########################################################################
# Hand-written cell LEF for FRIDA analog primitive cells
#
# These are simplified physical abstracts for the sg13_lv_nmos and
# sg13_lv_pmos devices as generated by flow/mosfet/primitive.py with
# default MosfetParams (nf=4, w=1, l=1, vth=LOW, source_tie=OFF, pr=2).
#
# Cell size: 3.020 x 3.060 um (from KLayout bbox in dbu with dbu=0.001)
# Row height: 3.060 um (= SITE height, cells tile into standard rows)
#
# Pin positions (track-aligned, 0.420 x 0.420 um to span Metal1 pitch):
#   s:    (0.000, 0.000) -> (0.420, 0.420)   bottom-left (source/vss)
#   d:    (2.600, 0.630) -> (3.020, 1.050)   right-side  (drain)
#   g:    (0.000, 1.320) -> (0.420, 1.740)   left-side   (gate)
#   b:    (0.000, 2.640) -> (0.420, 3.060)   top-left    (bulk/vdd)
#
# NOTE: This is a temporary hand-written file for verifying that
# OpenROAD can read our design. The real flow will generate this
# from vlsir.raw via Layout21's LefExporter.
########################################################################

VERSION 5.7 ;
BUSBITCHARS "[]" ;
DIVIDERCHAR "/" ;

SITE unit
  SYMMETRY Y ;
  CLASS CORE ;
  SIZE 0.005 BY 3.060 ;
END unit

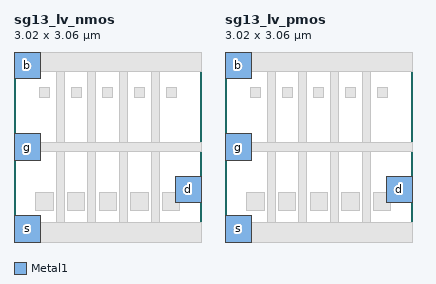
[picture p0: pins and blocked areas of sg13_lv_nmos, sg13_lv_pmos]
MACRO sg13_lv_nmos
  CLASS CORE ;
  ORIGIN 0 0 ;
  FOREIGN sg13_lv_nmos 0 0 ;
  SYMMETRY X Y ;
  SITE unit ;
  SIZE 3.020 BY 3.060 ;

  PIN d
    DIRECTION INOUT ;
    USE SIGNAL ;
    PORT
      LAYER Metal1 ;
        RECT 2.600 0.630 3.020 1.050 ;
    END
  END d

  PIN g
    DIRECTION INPUT ;
    USE SIGNAL ;
    PORT
      LAYER Metal1 ;
        RECT 0.000 1.320 0.420 1.740 ;
    END
  END g

  PIN s
    DIRECTION INOUT ;
    USE SIGNAL ;
    PORT
      LAYER Metal1 ;
        RECT 0.000 0.000 0.420 0.420 ;
    END
  END s

  PIN b
    DIRECTION INOUT ;
    USE SIGNAL ;
    PORT
      LAYER Metal1 ;
        RECT 0.000 2.640 0.420 3.060 ;
    END
  END b

  OBS
    LAYER GatPoly ;
      RECT 0.680 0.320 0.810 2.740 ;
      RECT 1.190 0.320 1.320 2.740 ;
      RECT 1.700 0.320 1.830 2.740 ;
      RECT 2.210 0.320 2.340 2.740 ;
    LAYER Cont ;
      RECT 0.410 0.570 0.570 0.730 ;
      RECT 0.410 2.330 0.570 2.490 ;
      RECT 0.920 0.570 1.080 0.730 ;
      RECT 0.920 2.330 1.080 2.490 ;
      RECT 1.430 0.570 1.590 0.730 ;
      RECT 1.430 2.330 1.590 2.490 ;
      RECT 1.940 0.570 2.100 0.730 ;
      RECT 1.940 2.330 2.100 2.490 ;
      RECT 2.450 0.570 2.610 0.730 ;
      RECT 2.450 2.330 2.610 2.490 ;
    LAYER Metal1 ;
      RECT 0.000 0.000 3.020 0.320 ;
      RECT 0.000 1.450 3.020 1.610 ;
      RECT 0.000 2.740 3.020 3.060 ;
      RECT 0.350 0.510 0.630 0.790 ;
      RECT 0.860 0.510 1.140 0.790 ;
      RECT 1.370 0.510 1.650 0.790 ;
      RECT 1.880 0.510 2.160 0.790 ;
      RECT 2.390 0.510 2.670 0.790 ;
  END

END sg13_lv_nmos

MACRO sg13_lv_pmos
  CLASS CORE ;
  ORIGIN 0 0 ;
  FOREIGN sg13_lv_pmos 0 0 ;
  SYMMETRY X Y ;
  SITE unit ;
  SIZE 3.020 BY 3.060 ;

  PIN d
    DIRECTION INOUT ;
    USE SIGNAL ;
    PORT
      LAYER Metal1 ;
        RECT 2.600 0.630 3.020 1.050 ;
    END
  END d

  PIN g
    DIRECTION INPUT ;
    USE SIGNAL ;
    PORT
      LAYER Metal1 ;
        RECT 0.000 1.320 0.420 1.740 ;
    END
  END g

  PIN s
    DIRECTION INOUT ;
    USE SIGNAL ;
    PORT
      LAYER Metal1 ;
        RECT 0.000 0.000 0.420 0.420 ;
    END
  END s

  PIN b
    DIRECTION INOUT ;
    USE SIGNAL ;
    PORT
      LAYER Metal1 ;
        RECT 0.000 2.640 0.420 3.060 ;
    END
  END b

  OBS
    LAYER GatPoly ;
      RECT 0.680 0.320 0.810 2.740 ;
      RECT 1.190 0.320 1.320 2.740 ;
      RECT 1.700 0.320 1.830 2.740 ;
      RECT 2.210 0.320 2.340 2.740 ;
    LAYER Cont ;
      RECT 0.410 0.570 0.570 0.730 ;
      RECT 0.410 2.330 0.570 2.490 ;
      RECT 0.920 0.570 1.080 0.730 ;
      RECT 0.920 2.330 1.080 2.490 ;
      RECT 1.430 0.570 1.590 0.730 ;
      RECT 1.430 2.330 1.590 2.490 ;
      RECT 1.940 0.570 2.100 0.730 ;
      RECT 1.940 2.330 2.100 2.490 ;
      RECT 2.450 0.570 2.610 0.730 ;
      RECT 2.450 2.330 2.610 2.490 ;
    LAYER Metal1 ;
      RECT 0.000 0.000 3.020 0.320 ;
      RECT 0.000 1.450 3.020 1.610 ;
      RECT 0.000 2.740 3.020 3.060 ;
      RECT 0.350 0.510 0.630 0.790 ;
      RECT 0.860 0.510 1.140 0.790 ;
      RECT 1.370 0.510 1.650 0.790 ;
      RECT 1.880 0.510 2.160 0.790 ;
      RECT 2.390 0.510 2.670 0.790 ;
  END

END sg13_lv_pmos

END LIBRARY
